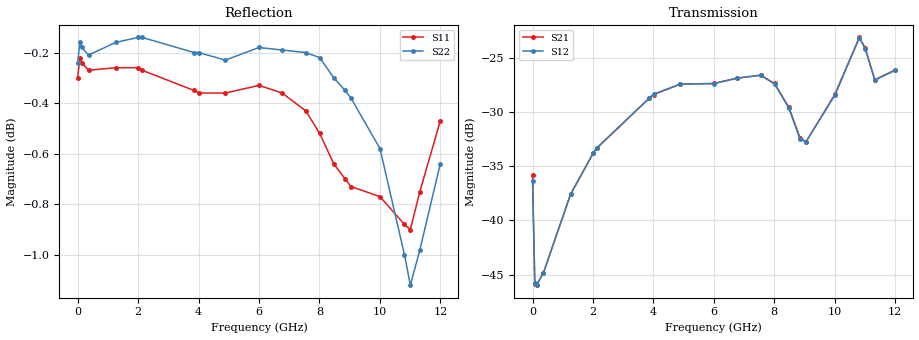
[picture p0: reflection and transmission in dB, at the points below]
!Agilent Technologies,E5071C,MY46418240,A.11.23
!Date: Wed Dec 09 09:54:06 2020
!Data & Calibration Information:
!Freq	S11:SOLT2(ON)	S21:SOLT2(ON)	S12:SOLT2(ON)	S22:SOLT2(ON)
!PortZ  Port1:50+j0  Port2:50+j0
!Above PortZ is port z conversion or system Z0 setting when saving the data.
!When reading, reference impedance value at option line is always used.
# Hz S dB R 50
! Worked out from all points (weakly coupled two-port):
!   801 points, 300 kHz to 12 GHz, reference 50 ohm
!   highest |S21| = -23.12 dB at 10.82 GHz (marker M1); lowest = -46.0 dB at 135.3 MHz (marker M2)
!   lowest |S11| = -0.9 dB at 11.01 GHz (marker M3), VSWR 19.26, Z = 7.12 + j65.8 ohm
!   |S11| at or under -10 dB: nowhere
!   |S22| runs from -1.1 to -0.1 dB; largest |S21 - S12| = 0.0013
!   S11 on the Smith chart (normalised r, x): 300 kHz: 0.02, -0.00; 2.13 GHz: 0.02, +0.20; 3.855 GHz: 0.02, +0.42; 6.765 GHz: 0.03, +0.67; 9.045 GHz: 0.09, +1.02; 12 GHz: 0.09, +1.49
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300000  -0.30 -179.8  -35.84 -18.4  -36.37 -18.5  -0.24 -179.9
7.529812e7  -0.22 178.9  -45.84 1.7  -45.79 2.0  -0.16 179.1
1.352966e8  -0.24 178.2  -45.96 8.5  -45.95 8.9  -0.18 178.6
3.60291e8  -0.27 176.1  -44.83 30.9  -44.83 30.7  -0.21 177.3
1.260268e9  -0.26 168.1  -37.59 59.9  -37.56 59.8  -0.16 172.7
2.01025e9  -0.26 159.3  -33.79 60.1  -33.77 59.9  -0.14 167.3
2.130247e9  -0.27 157.7  -33.34 59.3  -33.29 59.4  -0.14 166.4
3.855204e9  -0.35 134.6  -28.74 50.5  -28.74 50.6  -0.20 152.5
4.0052e9  -0.36 132.4  -28.40 48.6  -28.35 48.7  -0.20 150.7
4.890178e9  -0.36 121.8  -27.43 37.0  -27.42 37.1  -0.23 139.7
6.00015e9  -0.33 117.2  -27.37 28.9  -27.38 28.9  -0.18 132.1
6.765131e9  -0.36 112.0  -26.87 23.6  -26.89 23.6  -0.19 126.1
7.545111e9  -0.43 105.9  -26.61 11.8  -26.60 11.7  -0.20 121.7
8.0101e9  -0.52 102.0  -27.36 1.4  -27.43 1.4  -0.22 120.8
8.475088e9  -0.64 96.7  -29.53 -4.8  -29.61 -4.9  -0.30 119.9
8.850079e9  -0.70 91.4  -32.35 3.7  -32.49 4.1  -0.35 117.0
9.045074e9  -0.73 88.7  -32.77 18.3  -32.76 17.8  -0.38 115.4
1.000505e10  -0.77 81.1  -28.36 37.9  -28.45 37.8  -0.58 109.3
1.081503e10  -0.88 75.9  -23.12 11.2  -23.15 11.4  -1.00 107.4
1.101002e10  -0.90 74.1  -24.12 -2.9  -24.20 -3.0  -1.12 107.0
1.132502e10  -0.75 71.5  -27.02 -4.3  -27.06 -4.1  -0.98 104.0
1.2e10  -0.47 67.7  -26.11 -7.9  -26.16 -8.2  -0.64 95.6
